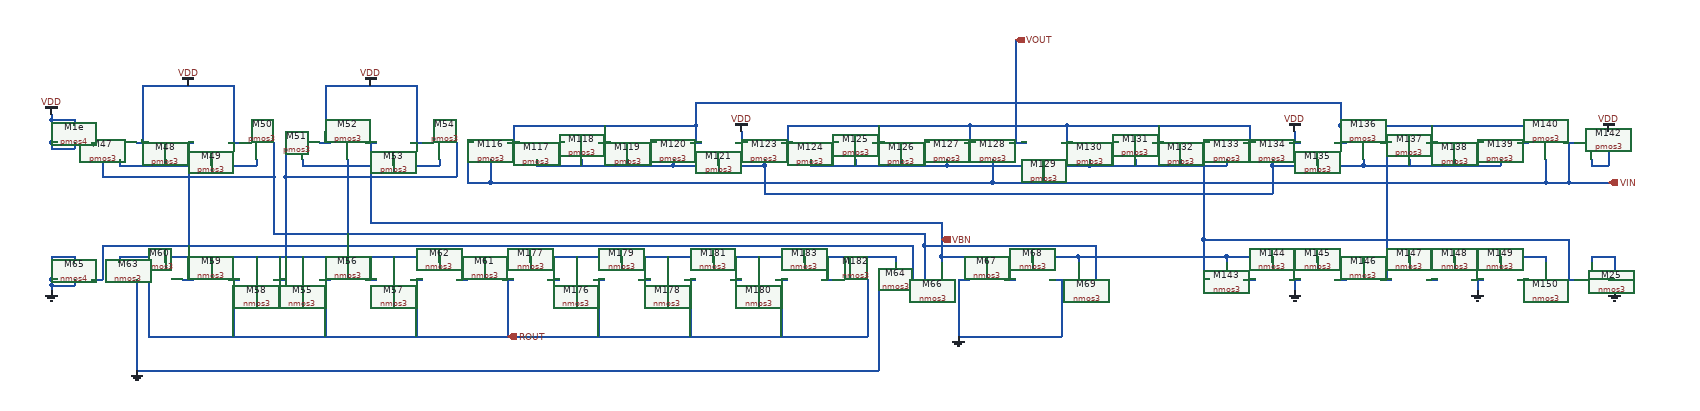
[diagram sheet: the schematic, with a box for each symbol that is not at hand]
v {xschem version=3.4.3 file_version=1.2
}
G {}
K {}
V {}
S {}
E {}
N -2510 230 -2510 240 {
lab=#net1}
N -2510 240 -2270 240 {
lab=#net1}
N -2270 230 -2270 240 {
lab=#net1}
N -2350 230 -2350 240 {
lab=#net1}
N -2430 230 -2430 240 {
lab=#net1}
N -2400 200 -2380 200 {
lab=#net1}
N -2390 200 -2390 240 {
lab=#net1}
N -2480 200 -2460 200 {
lab=VDD}
N -2320 200 -2300 200 {
lab=VDD}
N -2470 100 -2470 200 {
lab=VDD}
N -2470 100 -2310 100 {
lab=VDD}
N -2310 100 -2310 200 {
lab=VDD}
N -2540 200 -2540 260 {
lab=#net2}
N -2540 260 -2240 260 {
lab=#net2}
N -2240 200 -2240 260 {
lab=#net2}
N -2190 230 -2190 240 {
lab=#net2}
N -2190 240 -1950 240 {
lab=#net2}
N -1950 230 -1950 240 {
lab=#net2}
N -2030 230 -2030 240 {
lab=#net2}
N -2110 230 -2110 240 {
lab=#net2}
N -2080 200 -2060 200 {
lab=VBN}
N -2160 200 -2140 200 {
lab=VDD}
N -2000 200 -1980 200 {
lab=VDD}
N -2150 100 -2150 200 {
lab=VDD}
N -2150 100 -1990 100 {
lab=VDD}
N -1990 100 -1990 200 {
lab=VDD}
N -2220 200 -2220 260 {
lab=#net3}
N -2220 260 -1920 260 {
lab=#net3}
N -2190 400 -2190 410 {
lab=#net3}
N -2160 440 -2140 440 {
lab=VBN}
N -2110 400 -2110 410 {
lab=#net3}
N -2240 440 -2220 440 {
lab=#net3}
N -2080 440 -2060 440 {
lab=#net3}
N -2030 400 -2030 410 {
lab=#net3}
N -2270 400 -2270 410 {
lab=#net3}
N -2400 440 -2380 440 {
lab=#net3}
N -2320 440 -2300 440 {
lab=VBN}
N -2350 400 -2350 410 {
lab=#net3}
N -2430 400 -2430 410 {
lab=#net3}
N -1920 440 -1900 440 {
lab=#net3}
N -1870 400 -1870 410 {
lab=#net3}
N -1950 400 -1950 410 {
lab=#net3}
N -2000 440 -1980 440 {
lab=VBN}
N -2460 440 -2460 540 {
lab=VBN}
N -1990 440 -1990 540 {
lab=VBN}
N -2150 440 -2150 540 {
lab=VBN}
N -2310 440 -2310 540 {
lab=VBN}
N -2390 400 -2390 440 {
lab=#net3}
N -2230 400 -2230 440 {
lab=#net3}
N -2070 400 -2070 440 {
lab=#net3}
N -1910 400 -1910 440 {
lab=#net3}
N -2480 440 -2480 600 {
lab=GND}
N -1180 440 -1180 600 {
lab=GND}
N -2510 400 -2510 410 {
lab=#net3}
N -1150 400 -1150 410 {
lab=#net3}
N -1120 380 -1120 440 {
lab=#net1}
N -2540 380 -2540 440 {
lab=#net1}
N -2390 240 -2390 380 {
lab=#net1}
N -2590 160 -2590 170 {
lab=VDD}
N -2630 160 -2590 160 {
lab=VDD}
N -2630 160 -2630 200 {
lab=VDD}
N -2630 200 -2620 200 {
lab=VDD}
N -2590 200 -2590 210 {
lab=VDD}
N -2630 210 -2590 210 {
lab=VDD}
N -2630 200 -2630 210 {
lab=VDD}
N -2630 150 -2630 160 {
lab=VDD}
N -2560 200 -2540 200 {
lab=#net2}
N -2560 440 -2540 440 {
lab=#net1}
N -2590 440 -2590 450 {
lab=GND}
N -2630 450 -2590 450 {
lab=GND}
N -2630 440 -2630 450 {
lab=GND}
N -2630 440 -2620 440 {
lab=GND}
N -2590 400 -2590 410 {
lab=GND}
N -2630 400 -2590 400 {
lab=GND}
N -2630 400 -2630 440 {
lab=GND}
N -2630 450 -2630 460 {
lab=GND}
N -2220 260 -2220 400 {
lab=#net3}
N -1070 400 -1070 410 {
lab=VBN}
N -830 400 -830 410 {
lab=VBN}
N -990 400 -990 410 {
lab=VBN}
N -960 440 -940 440 {
lab=VBN}
N -910 400 -910 410 {
lab=VBN}
N -1070 400 -830 400 {
lab=VBN}
N -1100 380 -800 380 {
lab=#net2}
N -1100 380 -1100 440 {
lab=#net2}
N -860 440 -860 540 {
lab=GND}
N -1040 540 -860 540 {
lab=GND}
N -1040 440 -1040 540 {
lab=GND}
N -2070 200 -2070 280 {
lab=VBN}
N -2240 260 -2240 300 {
lab=#net2}
N -2110 240 -2110 300 {
lab=#net2}
N -1760 440 -1740 440 {
lab=#net3}
N -1710 400 -1710 410 {
lab=#net3}
N -1790 400 -1790 410 {
lab=#net3}
N -1840 440 -1820 440 {
lab=VBN}
N -1830 440 -1830 540 {
lab=VBN}
N -1750 400 -1750 440 {
lab=#net3}
N -1600 440 -1580 440 {
lab=#net3}
N -1550 400 -1550 410 {
lab=#net3}
N -1630 400 -1630 410 {
lab=#net3}
N -1680 440 -1660 440 {
lab=VBN}
N -1670 440 -1670 540 {
lab=VBN}
N -1590 400 -1590 440 {
lab=#net3}
N -1440 440 -1420 440 {
lab=#net3}
N -1390 400 -1390 410 {
lab=#net3}
N -1470 400 -1470 410 {
lab=#net3}
N -1520 440 -1500 440 {
lab=VBN}
N -1510 440 -1510 540 {
lab=VBN}
N -1430 400 -1430 440 {
lab=#net3}
N -1280 440 -1260 440 {
lab=#net3}
N -1230 400 -1230 410 {
lab=#net3}
N -1310 400 -1310 410 {
lab=#net3}
N -1360 440 -1340 440 {
lab=VBN}
N -1350 440 -1350 540 {
lab=VBN}
N -1270 400 -1270 440 {
lab=#net3}
N -1200 440 -1200 540 {
lab=VBN}
N -2460 540 -1200 540 {
lab=VBN}
N -2510 400 -1150 400 {
lab=#net3}
N -2480 600 -1180 600 {
lab=GND}
N -2540 380 -1120 380 {
lab=#net1}
N -2110 300 -2110 360 {
lab=#net2}
N -2240 300 -2240 360 {
lab=#net2}
N -1100 360 -1100 380 {
lab=#net2}
N -2070 340 -1070 340 {
lab=VBN}
N -2070 280 -2070 340 {
lab=VBN}
N -1070 340 -1070 400 {
lab=VBN}
N 70 400 70 410 {
lab=GND}
N 70 400 110 400 {
lab=GND}
N 100 440 110 440 {
lab=GND}
N 110 400 110 460 {
lab=GND}
N -1920 200 -1920 260 {
lab=#net3}
N -2240 360 -1100 360 {
lab=#net2}
N -1830 200 -1810 200 {
lab=#net4}
N -1750 200 -1730 200 {
lab=#net5}
N -1670 200 -1650 200 {
lab=#net4}
N -1590 200 -1570 200 {
lab=#net5}
N -1510 200 -1490 200 {
lab=#net4}
N -1430 200 -1410 200 {
lab=VDD}
N -1350 200 -1330 200 {
lab=#net6}
N -1270 200 -1250 200 {
lab=#net7}
N -1190 200 -1170 200 {
lab=#net6}
N -1110 200 -1090 200 {
lab=#net7}
N -1030 200 -1010 200 {
lab=#net6}
N -950 200 -930 200 {
lab=VOUT}
N -1900 200 -1890 200 {
lab=VIN}
N -1900 200 -1900 240 {
lab=VIN}
N -1860 230 -1860 240 {
lab=VIN}
N -1780 230 -1780 240 {
lab=#net5}
N -1700 230 -1700 240 {
lab=#net5}
N -1620 230 -1620 240 {
lab=#net5}
N -1540 230 -1540 240 {
lab=#net5}
N -1780 240 -1540 240 {
lab=#net5}
N -1820 170 -1820 200 {
lab=#net4}
N -1820 170 -1500 170 {
lab=#net4}
N -1500 170 -1500 200 {
lab=#net4}
N -1660 170 -1660 200 {
lab=#net4}
N -1740 200 -1740 240 {
lab=#net5}
N -1580 200 -1580 240 {
lab=#net5}
N -1540 240 -1380 240 {
lab=#net5}
N -1380 230 -1380 240 {
lab=#net5}
N -1460 230 -1460 240 {
lab=#net5}
N -1300 230 -1300 240 {
lab=#net7}
N -1300 240 -1060 240 {
lab=#net7}
N -1060 230 -1060 240 {
lab=#net7}
N -1220 230 -1220 240 {
lab=#net7}
N -1140 230 -1140 240 {
lab=#net7}
N -1420 180 -1420 200 {
lab=VDD}
N -1340 170 -1340 200 {
lab=#net6}
N -1340 170 -1020 170 {
lab=#net6}
N -1020 170 -1020 200 {
lab=#net6}
N -1180 170 -1180 200 {
lab=#net6}
N -1260 200 -1260 240 {
lab=#net7}
N -1100 200 -1100 240 {
lab=#net7}
N -860 200 -840 200 {
lab=#net6}
N -780 200 -760 200 {
lab=#net7}
N -700 200 -680 200 {
lab=#net6}
N -620 200 -600 200 {
lab=#net7}
N -540 200 -520 200 {
lab=#net6}
N -460 200 -440 200 {
lab=VDD}
N -380 200 -360 200 {
lab=#net4}
N -300 200 -280 200 {
lab=#net5}
N -220 200 -200 200 {
lab=#net4}
N -140 200 -120 200 {
lab=#net5}
N -60 200 -40 200 {
lab=#net4}
N 20 200 40 200 {
lab=VIN}
N -930 200 -920 200 {
lab=VOUT}
N -810 230 -810 240 {
lab=#net7}
N -730 230 -730 240 {
lab=#net7}
N -650 230 -650 240 {
lab=#net7}
N -570 230 -570 240 {
lab=#net7}
N -810 240 -570 240 {
lab=#net7}
N -850 170 -850 200 {
lab=#net6}
N -850 170 -530 170 {
lab=#net6}
N -530 170 -530 200 {
lab=#net6}
N -690 170 -690 200 {
lab=#net6}
N -770 200 -770 240 {
lab=#net7}
N -610 200 -610 240 {
lab=#net7}
N -410 230 -410 240 {
lab=#net5}
N -490 230 -490 240 {
lab=#net5}
N -330 230 -330 240 {
lab=#net5}
N -330 240 -90 240 {
lab=#net5}
N -90 230 -90 240 {
lab=#net5}
N -250 230 -250 240 {
lab=#net5}
N -170 230 -170 240 {
lab=#net5}
N -450 180 -450 200 {
lab=VDD}
N -370 170 -370 200 {
lab=#net4}
N -370 170 -50 170 {
lab=#net4}
N -50 170 -50 200 {
lab=#net4}
N -210 170 -210 200 {
lab=#net4}
N -290 200 -290 240 {
lab=#net5}
N -130 200 -130 240 {
lab=#net5}
N -490 240 -330 240 {
lab=#net5}
N -10 230 -10 240 {
lab=VIN}
N 30 200 30 240 {
lab=VIN}
N 70 230 70 240 {
lab=VDD}
N 70 240 100 240 {
lab=VDD}
N 100 200 100 240 {
lab=VDD}
N -540 440 -520 440 {
lab=#net8}
N -380 440 -360 440 {
lab=#net9}
N -460 440 -440 440 {
lab=GND}
N -220 440 -200 440 {
lab=#net10}
N -60 440 -40 440 {
lab=#net11}
N -140 440 -120 440 {
lab=GND}
N -300 440 -280 440 {
lab=#net5}
N -570 400 -570 410 {
lab=VBN}
N -490 400 -490 410 {
lab=VBN}
N -410 400 -410 410 {
lab=VBN}
N -330 400 -330 410 {
lab=VBN}
N -250 400 -250 410 {
lab=VBN}
N -170 400 -170 410 {
lab=VBN}
N -90 400 -90 410 {
lab=VBN}
N -10 400 -10 410 {
lab=VBN}
N -570 400 -10 400 {
lab=VBN}
N -450 440 -450 460 {
lab=GND}
N -130 440 -130 460 {
lab=GND}
N -1860 240 -1860 270 {
lab=VIN}
N -1900 240 -1900 270 {
lab=VIN}
N -1900 270 -1860 270 {
lab=VIN}
N -940 160 -940 200 {
lab=VOUT}
N -10 240 -10 270 {
lab=VIN}
N -980 270 -10 270 {
lab=VIN}
N 30 240 30 270 {
lab=VIN}
N -10 270 30 270 {
lab=VIN}
N -890 230 -890 270 {
lab=VIN}
N -1060 240 -810 240 {
lab=#net7}
N -980 230 -980 270 {
lab=VIN}
N 20 440 40 440 {
lab=#net7}
N -600 370 30 370 {
lab=#net7}
N 30 370 30 440 {
lab=#net7}
N -290 240 -290 430 {
lab=#net5}
N -610 440 -600 440 {
lab=#net7}
N -610 370 -610 440 {
lab=#net7}
N -610 370 -600 370 {
lab=#net7}
N -610 240 -610 360 {
lab=#net7}
N -1380 290 -490 290 {
lab=#net5}
N -490 240 -490 290 {
lab=#net5}
N -1860 270 -980 270 {
lab=VIN}
N -1380 240 -1380 290 {
lab=#net5}
N -1020 170 -850 170 {
lab=#net6}
N -1500 130 -1500 170 {
lab=#net4}
N -370 140 -370 170 {
lab=#net4}
N -370 130 -370 140 {
lab=#net4}
N -1500 130 -370 130 {
lab=#net4}
N 100 180 100 200 {
lab=VDD}
N -800 380 -800 440 {
lab=#net2}
N -940 20 -940 160 {
lab=VOUT}
N -610 360 -610 370 {
lab=#net7}
N -290 430 -290 440 {
lab=#net5}
N -830 400 -570 400 {
lab=VBN}
N -950 400 -950 440 {
lab=VBN}
N -880 440 -860 440 {
lab=GND}
N -1040 440 -1020 440 {
lab=GND}
N 30 270 100 270 {
lab=VIN}
C {madvlsi/pmos3.sym} -2510 200 3 0 {name=M47
L=\{L\}
W=\{W/2\}
body=VDD
nf=1
mult=1
ad="'int((nf+1)/2) * W/nf * 0.29'" 
pd="'2*int((nf+1)/2) * (W/nf + 0.29)'"
as="'int((nf+2)/2) * W/nf * 0.29'" 
ps="'2*int((nf+2)/2) * (W/nf + 0.29)'"
nrd="'0.29 / W'" nrs="'0.29 / W'"
sa=0 sb=0 sd=0
model=pfet_01v8
spiceprefix=X
}
C {madvlsi/pmos3.sym} -2430 200 3 0 {name=M48
L=\{L\}
W=\{W/2\}
body=VDD
nf=1
mult=1
ad="'int((nf+1)/2) * W/nf * 0.29'" 
pd="'2*int((nf+1)/2) * (W/nf + 0.29)'"
as="'int((nf+2)/2) * W/nf * 0.29'" 
ps="'2*int((nf+2)/2) * (W/nf + 0.29)'"
nrd="'0.29 / W'" nrs="'0.29 / W'"
sa=0 sb=0 sd=0
model=pfet_01v8
spiceprefix=X
}
C {madvlsi/pmos3.sym} -2350 200 3 0 {name=M49
L=\{L\}
W=\{W/2\}
body=VDD
nf=1
mult=1
ad="'int((nf+1)/2) * W/nf * 0.29'" 
pd="'2*int((nf+1)/2) * (W/nf + 0.29)'"
as="'int((nf+2)/2) * W/nf * 0.29'" 
ps="'2*int((nf+2)/2) * (W/nf + 0.29)'"
nrd="'0.29 / W'" nrs="'0.29 / W'"
sa=0 sb=0 sd=0
model=pfet_01v8
spiceprefix=X
}
C {madvlsi/pmos3.sym} -2270 200 3 0 {name=M50
L=\{L\}
W=\{W/2\}
body=VDD
nf=1
mult=1
ad="'int((nf+1)/2) * W/nf * 0.29'" 
pd="'2*int((nf+1)/2) * (W/nf + 0.29)'"
as="'int((nf+2)/2) * W/nf * 0.29'" 
ps="'2*int((nf+2)/2) * (W/nf + 0.29)'"
nrd="'0.29 / W'" nrs="'0.29 / W'"
sa=0 sb=0 sd=0
model=pfet_01v8
spiceprefix=X
}
C {madvlsi/pmos3.sym} -2190 200 3 0 {name=M51
L=\{L\}
W=\{W/2\}
body=VDD
nf=1
mult=1
ad="'int((nf+1)/2) * W/nf * 0.29'" 
pd="'2*int((nf+1)/2) * (W/nf + 0.29)'"
as="'int((nf+2)/2) * W/nf * 0.29'" 
ps="'2*int((nf+2)/2) * (W/nf + 0.29)'"
nrd="'0.29 / W'" nrs="'0.29 / W'"
sa=0 sb=0 sd=0
model=pfet_01v8
spiceprefix=X
}
C {madvlsi/pmos3.sym} -2110 200 3 0 {name=M52
L=\{L\}
W=\{W/2\}
body=VDD
nf=1
mult=1
ad="'int((nf+1)/2) * W/nf * 0.29'" 
pd="'2*int((nf+1)/2) * (W/nf + 0.29)'"
as="'int((nf+2)/2) * W/nf * 0.29'" 
ps="'2*int((nf+2)/2) * (W/nf + 0.29)'"
nrd="'0.29 / W'" nrs="'0.29 / W'"
sa=0 sb=0 sd=0
model=pfet_01v8
spiceprefix=X
}
C {madvlsi/pmos3.sym} -2030 200 3 0 {name=M53
L=\{L\}
W=\{W/2\}
body=VDD
nf=1
mult=1
ad="'int((nf+1)/2) * W/nf * 0.29'" 
pd="'2*int((nf+1)/2) * (W/nf + 0.29)'"
as="'int((nf+2)/2) * W/nf * 0.29'" 
ps="'2*int((nf+2)/2) * (W/nf + 0.29)'"
nrd="'0.29 / W'" nrs="'0.29 / W'"
sa=0 sb=0 sd=0
model=pfet_01v8
spiceprefix=X
}
C {madvlsi/pmos3.sym} -1950 200 3 0 {name=M54
L=\{L\}
W=\{W/2\}
body=VDD
nf=1
mult=1
ad="'int((nf+1)/2) * W/nf * 0.29'" 
pd="'2*int((nf+1)/2) * (W/nf + 0.29)'"
as="'int((nf+2)/2) * W/nf * 0.29'" 
ps="'2*int((nf+2)/2) * (W/nf + 0.29)'"
nrd="'0.29 / W'" nrs="'0.29 / W'"
sa=0 sb=0 sd=0
model=pfet_01v8
spiceprefix=X
}
C {madvlsi/nmos3.sym} -2190 440 1 0 {name=M55
L=\{L\}
W=\{W/2\}
body=GND
nf=1
mult=1
ad="'int((nf+1)/2) * W/nf * 0.29'" 
pd="'2*int((nf+1)/2) * (W/nf + 0.29)'"
as="'int((nf+2)/2) * W/nf * 0.29'" 
ps="'2*int((nf+2)/2) * (W/nf + 0.29)'"
nrd="'0.29 / W'" nrs="'0.29 / W'"
sa=0 sb=0 sd=0
model=nfet_01v8
spiceprefix=X
}
C {madvlsi/nmos3.sym} -2110 440 1 0 {name=M56
L=\{L\}
W=\{W/2\}
body=GND
nf=1
mult=1
ad="'int((nf+1)/2) * W/nf * 0.29'" 
pd="'2*int((nf+1)/2) * (W/nf + 0.29)'"
as="'int((nf+2)/2) * W/nf * 0.29'" 
ps="'2*int((nf+2)/2) * (W/nf + 0.29)'"
nrd="'0.29 / W'" nrs="'0.29 / W'"
sa=0 sb=0 sd=0
model=nfet_01v8
spiceprefix=X
}
C {madvlsi/nmos3.sym} -2030 440 1 0 {name=M57
L=\{L\}
W=\{W/2\}
body=GND
nf=1
mult=1
ad="'int((nf+1)/2) * W/nf * 0.29'" 
pd="'2*int((nf+1)/2) * (W/nf + 0.29)'"
as="'int((nf+2)/2) * W/nf * 0.29'" 
ps="'2*int((nf+2)/2) * (W/nf + 0.29)'"
nrd="'0.29 / W'" nrs="'0.29 / W'"
sa=0 sb=0 sd=0
model=nfet_01v8
spiceprefix=X
}
C {madvlsi/nmos3.sym} -2270 440 1 0 {name=M58
L=\{L\}
W=\{W/2\}
body=GND
nf=1
mult=1
ad="'int((nf+1)/2) * W/nf * 0.29'" 
pd="'2*int((nf+1)/2) * (W/nf + 0.29)'"
as="'int((nf+2)/2) * W/nf * 0.29'" 
ps="'2*int((nf+2)/2) * (W/nf + 0.29)'"
nrd="'0.29 / W'" nrs="'0.29 / W'"
sa=0 sb=0 sd=0
model=nfet_01v8
spiceprefix=X
}
C {madvlsi/nmos3.sym} -2350 440 1 0 {name=M59
L=\{L\}
W=\{W/2\}
body=GND
nf=1
mult=1
ad="'int((nf+1)/2) * W/nf * 0.29'" 
pd="'2*int((nf+1)/2) * (W/nf + 0.29)'"
as="'int((nf+2)/2) * W/nf * 0.29'" 
ps="'2*int((nf+2)/2) * (W/nf + 0.29)'"
nrd="'0.29 / W'" nrs="'0.29 / W'"
sa=0 sb=0 sd=0
model=nfet_01v8
spiceprefix=X
}
C {madvlsi/nmos3.sym} -2430 440 1 0 {name=M60
L=\{L\}
W=\{W/2\}
body=GND
nf=1
mult=1
ad="'int((nf+1)/2) * W/nf * 0.29'" 
pd="'2*int((nf+1)/2) * (W/nf + 0.29)'"
as="'int((nf+2)/2) * W/nf * 0.29'" 
ps="'2*int((nf+2)/2) * (W/nf + 0.29)'"
nrd="'0.29 / W'" nrs="'0.29 / W'"
sa=0 sb=0 sd=0
model=nfet_01v8
spiceprefix=X
}
C {madvlsi/nmos3.sym} -1870 440 1 0 {name=M61
L=\{L\}
W=\{W/2\}
body=GND
nf=1
mult=1
ad="'int((nf+1)/2) * W/nf * 0.29'" 
pd="'2*int((nf+1)/2) * (W/nf + 0.29)'"
as="'int((nf+2)/2) * W/nf * 0.29'" 
ps="'2*int((nf+2)/2) * (W/nf + 0.29)'"
nrd="'0.29 / W'" nrs="'0.29 / W'"
sa=0 sb=0 sd=0
model=nfet_01v8
spiceprefix=X
}
C {madvlsi/nmos3.sym} -1950 440 1 0 {name=M62
L=\{L\}
W=\{W/2\}
body=GND
nf=1
mult=1
ad="'int((nf+1)/2) * W/nf * 0.29'" 
pd="'2*int((nf+1)/2) * (W/nf + 0.29)'"
as="'int((nf+2)/2) * W/nf * 0.29'" 
ps="'2*int((nf+2)/2) * (W/nf + 0.29)'"
nrd="'0.29 / W'" nrs="'0.29 / W'"
sa=0 sb=0 sd=0
model=nfet_01v8
spiceprefix=X
}
C {madvlsi/nmos3.sym} -2510 440 1 0 {name=M63
L=\{L\}
W=\{W/2\}
body=GND
nf=1
mult=1
ad="'int((nf+1)/2) * W/nf * 0.29'" 
pd="'2*int((nf+1)/2) * (W/nf + 0.29)'"
as="'int((nf+2)/2) * W/nf * 0.29'" 
ps="'2*int((nf+2)/2) * (W/nf + 0.29)'"
nrd="'0.29 / W'" nrs="'0.29 / W'"
sa=0 sb=0 sd=0
model=nfet_01v8
spiceprefix=X
}
C {madvlsi/nmos3.sym} -1150 440 1 0 {name=M64
L=\{L\}
W=\{W/2\}
body=GND
nf=1
mult=1
ad="'int((nf+1)/2) * W/nf * 0.29'" 
pd="'2*int((nf+1)/2) * (W/nf + 0.29)'"
as="'int((nf+2)/2) * W/nf * 0.29'" 
ps="'2*int((nf+2)/2) * (W/nf + 0.29)'"
nrd="'0.29 / W'" nrs="'0.29 / W'"
sa=0 sb=0 sd=0
model=nfet_01v8
spiceprefix=X
}
C {madvlsi/pmos4.sym} -2590 200 1 0 {name=M1e
L=\{L\}
W=\{W/2\}
nf=1
mult=1
ad="'int((nf+1)/2) * W/nf * 0.29'" 
pd="'2*int((nf+1)/2) * (W/nf + 0.29)'"
as="'int((nf+2)/2) * W/nf * 0.29'" 
ps="'2*int((nf+2)/2) * (W/nf + 0.29)'"
nrd="'0.29 / W'" nrs="'0.29 / W'"
sa=0 sb=0 sd=0
model=pfet_01v8
spiceprefix=X
}
C {madvlsi/vdd.sym} -2630 150 0 0 {name=l24 lab=VDD}
C {madvlsi/nmos4.sym} -2590 440 1 0 {name=M65
L=\{L\}
W=\{W/2\}
nf=1 
mult=1
ad="'int((nf+1)/2) * W/nf * 0.29'" 
pd="'2*int((nf+1)/2) * (W/nf + 0.29)'"
as="'int((nf+2)/2) * W/nf * 0.29'" 
ps="'2*int((nf+2)/2) * (W/nf + 0.29)'"
nrd="'0.29 / W'" nrs="'0.29 / W'"
sa=0 sb=0 sd=0
model=nfet_01v8
spiceprefix=X
}
C {madvlsi/gnd.sym} -2630 460 0 0 {name=l33 lab=GND}
C {madvlsi/nmos3.sym} -1070 440 1 0 {name=M66
L=\{L\}
W=\{W/2\}
body=GND
nf=1
mult=1
ad="'int((nf+1)/2) * W/nf * 0.29'" 
pd="'2*int((nf+1)/2) * (W/nf + 0.29)'"
as="'int((nf+2)/2) * W/nf * 0.29'" 
ps="'2*int((nf+2)/2) * (W/nf + 0.29)'"
nrd="'0.29 / W'" nrs="'0.29 / W'"
sa=0 sb=0 sd=0
model=nfet_01v8
spiceprefix=X
}
C {madvlsi/nmos3.sym} -990 440 1 0 {name=M67
L=\{L\}
W=\{W/2\}
body=GND
nf=1
mult=1
ad="'int((nf+1)/2) * W/nf * 0.29'" 
pd="'2*int((nf+1)/2) * (W/nf + 0.29)'"
as="'int((nf+2)/2) * W/nf * 0.29'" 
ps="'2*int((nf+2)/2) * (W/nf + 0.29)'"
nrd="'0.29 / W'" nrs="'0.29 / W'"
sa=0 sb=0 sd=0
model=nfet_01v8
spiceprefix=X
}
C {madvlsi/nmos3.sym} -910 440 1 0 {name=M68
L=\{L\}
W=\{W/2\}
body=GND
nf=1
mult=1
ad="'int((nf+1)/2) * W/nf * 0.29'" 
pd="'2*int((nf+1)/2) * (W/nf + 0.29)'"
as="'int((nf+2)/2) * W/nf * 0.29'" 
ps="'2*int((nf+2)/2) * (W/nf + 0.29)'"
nrd="'0.29 / W'" nrs="'0.29 / W'"
sa=0 sb=0 sd=0
model=nfet_01v8
spiceprefix=X
}
C {madvlsi/nmos3.sym} -830 440 1 0 {name=M69
L=\{L\}
W=\{W/2\}
body=GND
nf=1
mult=1
ad="'int((nf+1)/2) * W/nf * 0.29'" 
pd="'2*int((nf+1)/2) * (W/nf + 0.29)'"
as="'int((nf+2)/2) * W/nf * 0.29'" 
ps="'2*int((nf+2)/2) * (W/nf + 0.29)'"
nrd="'0.29 / W'" nrs="'0.29 / W'"
sa=0 sb=0 sd=0
model=nfet_01v8
spiceprefix=X
}
C {madvlsi/nmos3.sym} -1710 440 1 0 {name=M176
L=\{L\}
W=\{W/2\}
body=GND
nf=1
mult=1
ad="'int((nf+1)/2) * W/nf * 0.29'" 
pd="'2*int((nf+1)/2) * (W/nf + 0.29)'"
as="'int((nf+2)/2) * W/nf * 0.29'" 
ps="'2*int((nf+2)/2) * (W/nf + 0.29)'"
nrd="'0.29 / W'" nrs="'0.29 / W'"
sa=0 sb=0 sd=0
model=nfet_01v8
spiceprefix=X
}
C {madvlsi/nmos3.sym} -1790 440 1 0 {name=M177
L=\{L\}
W=\{W/2\}
body=GND
nf=1
mult=1
ad="'int((nf+1)/2) * W/nf * 0.29'" 
pd="'2*int((nf+1)/2) * (W/nf + 0.29)'"
as="'int((nf+2)/2) * W/nf * 0.29'" 
ps="'2*int((nf+2)/2) * (W/nf + 0.29)'"
nrd="'0.29 / W'" nrs="'0.29 / W'"
sa=0 sb=0 sd=0
model=nfet_01v8
spiceprefix=X
}
C {madvlsi/nmos3.sym} -1550 440 1 0 {name=M178
L=\{L\}
W=\{W/2\}
body=GND
nf=1
mult=1
ad="'int((nf+1)/2) * W/nf * 0.29'" 
pd="'2*int((nf+1)/2) * (W/nf + 0.29)'"
as="'int((nf+2)/2) * W/nf * 0.29'" 
ps="'2*int((nf+2)/2) * (W/nf + 0.29)'"
nrd="'0.29 / W'" nrs="'0.29 / W'"
sa=0 sb=0 sd=0
model=nfet_01v8
spiceprefix=X
}
C {madvlsi/nmos3.sym} -1630 440 1 0 {name=M179
L=\{L\}
W=\{W/2\}
body=GND
nf=1
mult=1
ad="'int((nf+1)/2) * W/nf * 0.29'" 
pd="'2*int((nf+1)/2) * (W/nf + 0.29)'"
as="'int((nf+2)/2) * W/nf * 0.29'" 
ps="'2*int((nf+2)/2) * (W/nf + 0.29)'"
nrd="'0.29 / W'" nrs="'0.29 / W'"
sa=0 sb=0 sd=0
model=nfet_01v8
spiceprefix=X
}
C {madvlsi/nmos3.sym} -1390 440 1 0 {name=M180
L=\{L\}
W=\{W/2\}
body=GND
nf=1
mult=1
ad="'int((nf+1)/2) * W/nf * 0.29'" 
pd="'2*int((nf+1)/2) * (W/nf + 0.29)'"
as="'int((nf+2)/2) * W/nf * 0.29'" 
ps="'2*int((nf+2)/2) * (W/nf + 0.29)'"
nrd="'0.29 / W'" nrs="'0.29 / W'"
sa=0 sb=0 sd=0
model=nfet_01v8
spiceprefix=X
}
C {madvlsi/nmos3.sym} -1470 440 1 0 {name=M181
L=\{L\}
W=\{W/2\}
body=GND
nf=1
mult=1
ad="'int((nf+1)/2) * W/nf * 0.29'" 
pd="'2*int((nf+1)/2) * (W/nf + 0.29)'"
as="'int((nf+2)/2) * W/nf * 0.29'" 
ps="'2*int((nf+2)/2) * (W/nf + 0.29)'"
nrd="'0.29 / W'" nrs="'0.29 / W'"
sa=0 sb=0 sd=0
model=nfet_01v8
spiceprefix=X
}
C {madvlsi/nmos3.sym} -1230 440 1 0 {name=M182
L=\{L\}
W=\{W/2\}
body=GND
nf=1
mult=1
ad="'int((nf+1)/2) * W/nf * 0.29'" 
pd="'2*int((nf+1)/2) * (W/nf + 0.29)'"
as="'int((nf+2)/2) * W/nf * 0.29'" 
ps="'2*int((nf+2)/2) * (W/nf + 0.29)'"
nrd="'0.29 / W'" nrs="'0.29 / W'"
sa=0 sb=0 sd=0
model=nfet_01v8
spiceprefix=X
}
C {madvlsi/nmos3.sym} -1310 440 1 0 {name=M183
L=\{L\}
W=\{W/2\}
body=GND
nf=1
mult=1
ad="'int((nf+1)/2) * W/nf * 0.29'" 
pd="'2*int((nf+1)/2) * (W/nf + 0.29)'"
as="'int((nf+2)/2) * W/nf * 0.29'" 
ps="'2*int((nf+2)/2) * (W/nf + 0.29)'"
nrd="'0.29 / W'" nrs="'0.29 / W'"
sa=0 sb=0 sd=0
model=nfet_01v8
spiceprefix=X
}
C {madvlsi/gnd.sym} -2480 600 0 0 {name=l41 lab=GND}
C {madvlsi/gnd.sym} -1040 540 0 0 {name=l43 lab=GND}
C {madvlsi/vdd.sym} -2390 100 0 0 {name=l45 lab=VDD}
C {madvlsi/vdd.sym} -2070 100 0 0 {name=l46 lab=VDD}
C {madvlsi/gnd.sym} 110 460 0 0 {name=l25 lab=GND}
C {madvlsi/pmos3.sym} -1860 200 3 0 {name=M116
L=\{L\}
W=\{W/2\}
body=VDD
nf=1
mult=1
ad="'int((nf+1)/2) * W/nf * 0.29'" 
pd="'2*int((nf+1)/2) * (W/nf + 0.29)'"
as="'int((nf+2)/2) * W/nf * 0.29'" 
ps="'2*int((nf+2)/2) * (W/nf + 0.29)'"
nrd="'0.29 / W'" nrs="'0.29 / W'"
sa=0 sb=0 sd=0
model=pfet_01v8
spiceprefix=X
}
C {madvlsi/pmos3.sym} -1780 200 3 0 {name=M117
L=\{L\}
W=\{W/2\}
body=VDD
nf=1
mult=1
ad="'int((nf+1)/2) * W/nf * 0.29'" 
pd="'2*int((nf+1)/2) * (W/nf + 0.29)'"
as="'int((nf+2)/2) * W/nf * 0.29'" 
ps="'2*int((nf+2)/2) * (W/nf + 0.29)'"
nrd="'0.29 / W'" nrs="'0.29 / W'"
sa=0 sb=0 sd=0
model=pfet_01v8
spiceprefix=X
}
C {madvlsi/pmos3.sym} -1700 200 3 0 {name=M118
L=\{L\}
W=\{W/2\}
body=VDD
nf=1
mult=1
ad="'int((nf+1)/2) * W/nf * 0.29'" 
pd="'2*int((nf+1)/2) * (W/nf + 0.29)'"
as="'int((nf+2)/2) * W/nf * 0.29'" 
ps="'2*int((nf+2)/2) * (W/nf + 0.29)'"
nrd="'0.29 / W'" nrs="'0.29 / W'"
sa=0 sb=0 sd=0
model=pfet_01v8
spiceprefix=X
}
C {madvlsi/pmos3.sym} -1620 200 3 0 {name=M119
L=\{L\}
W=\{W/2\}
body=VDD
nf=1
mult=1
ad="'int((nf+1)/2) * W/nf * 0.29'" 
pd="'2*int((nf+1)/2) * (W/nf + 0.29)'"
as="'int((nf+2)/2) * W/nf * 0.29'" 
ps="'2*int((nf+2)/2) * (W/nf + 0.29)'"
nrd="'0.29 / W'" nrs="'0.29 / W'"
sa=0 sb=0 sd=0
model=pfet_01v8
spiceprefix=X
}
C {madvlsi/pmos3.sym} -1540 200 3 0 {name=M120
L=\{L\}
W=\{W/2\}
body=VDD
nf=1
mult=1
ad="'int((nf+1)/2) * W/nf * 0.29'" 
pd="'2*int((nf+1)/2) * (W/nf + 0.29)'"
as="'int((nf+2)/2) * W/nf * 0.29'" 
ps="'2*int((nf+2)/2) * (W/nf + 0.29)'"
nrd="'0.29 / W'" nrs="'0.29 / W'"
sa=0 sb=0 sd=0
model=pfet_01v8
spiceprefix=X
}
C {madvlsi/pmos3.sym} -1460 200 3 0 {name=M121
L=\{L\}
W=\{W/2\}
body=VDD
nf=1
mult=1
ad="'int((nf+1)/2) * W/nf * 0.29'" 
pd="'2*int((nf+1)/2) * (W/nf + 0.29)'"
as="'int((nf+2)/2) * W/nf * 0.29'" 
ps="'2*int((nf+2)/2) * (W/nf + 0.29)'"
nrd="'0.29 / W'" nrs="'0.29 / W'"
sa=0 sb=0 sd=0
model=pfet_01v8
spiceprefix=X
}
C {madvlsi/pmos3.sym} -1380 200 3 0 {name=M123
L=\{L\}
W=\{W/2\}
body=VDD
nf=1
mult=1
ad="'int((nf+1)/2) * W/nf * 0.29'" 
pd="'2*int((nf+1)/2) * (W/nf + 0.29)'"
as="'int((nf+2)/2) * W/nf * 0.29'" 
ps="'2*int((nf+2)/2) * (W/nf + 0.29)'"
nrd="'0.29 / W'" nrs="'0.29 / W'"
sa=0 sb=0 sd=0
model=pfet_01v8
spiceprefix=X
}
C {madvlsi/pmos3.sym} -1300 200 3 0 {name=M124
L=\{L\}
W=\{W/2\}
body=VDD
nf=1
mult=1
ad="'int((nf+1)/2) * W/nf * 0.29'" 
pd="'2*int((nf+1)/2) * (W/nf + 0.29)'"
as="'int((nf+2)/2) * W/nf * 0.29'" 
ps="'2*int((nf+2)/2) * (W/nf + 0.29)'"
nrd="'0.29 / W'" nrs="'0.29 / W'"
sa=0 sb=0 sd=0
model=pfet_01v8
spiceprefix=X
}
C {madvlsi/pmos3.sym} -1220 200 3 0 {name=M125
L=\{L\}
W=\{W/2\}
body=VDD
nf=1
mult=1
ad="'int((nf+1)/2) * W/nf * 0.29'" 
pd="'2*int((nf+1)/2) * (W/nf + 0.29)'"
as="'int((nf+2)/2) * W/nf * 0.29'" 
ps="'2*int((nf+2)/2) * (W/nf + 0.29)'"
nrd="'0.29 / W'" nrs="'0.29 / W'"
sa=0 sb=0 sd=0
model=pfet_01v8
spiceprefix=X
}
C {madvlsi/pmos3.sym} -1140 200 3 0 {name=M126
L=\{L\}
W=\{W/2\}
body=VDD
nf=1
mult=1
ad="'int((nf+1)/2) * W/nf * 0.29'" 
pd="'2*int((nf+1)/2) * (W/nf + 0.29)'"
as="'int((nf+2)/2) * W/nf * 0.29'" 
ps="'2*int((nf+2)/2) * (W/nf + 0.29)'"
nrd="'0.29 / W'" nrs="'0.29 / W'"
sa=0 sb=0 sd=0
model=pfet_01v8
spiceprefix=X
}
C {madvlsi/pmos3.sym} -1060 200 3 0 {name=M127
L=\{L\}
W=\{W/2\}
body=VDD
nf=1
mult=1
ad="'int((nf+1)/2) * W/nf * 0.29'" 
pd="'2*int((nf+1)/2) * (W/nf + 0.29)'"
as="'int((nf+2)/2) * W/nf * 0.29'" 
ps="'2*int((nf+2)/2) * (W/nf + 0.29)'"
nrd="'0.29 / W'" nrs="'0.29 / W'"
sa=0 sb=0 sd=0
model=pfet_01v8
spiceprefix=X
}
C {madvlsi/pmos3.sym} -980 200 3 0 {name=M128
L=\{L\}
W=\{W/2\}
body=VDD
nf=1
mult=1
ad="'int((nf+1)/2) * W/nf * 0.29'" 
pd="'2*int((nf+1)/2) * (W/nf + 0.29)'"
as="'int((nf+2)/2) * W/nf * 0.29'" 
ps="'2*int((nf+2)/2) * (W/nf + 0.29)'"
nrd="'0.29 / W'" nrs="'0.29 / W'"
sa=0 sb=0 sd=0
model=pfet_01v8
spiceprefix=X
}
C {madvlsi/vdd.sym} -1420 180 0 0 {name=l29 lab=VDD}
C {madvlsi/pmos3.sym} -890 200 3 0 {name=M129
L=\{L\}
W=\{W/2\}
body=VDD
nf=1
mult=1
ad="'int((nf+1)/2) * W/nf * 0.29'" 
pd="'2*int((nf+1)/2) * (W/nf + 0.29)'"
as="'int((nf+2)/2) * W/nf * 0.29'" 
ps="'2*int((nf+2)/2) * (W/nf + 0.29)'"
nrd="'0.29 / W'" nrs="'0.29 / W'"
sa=0 sb=0 sd=0
model=pfet_01v8
spiceprefix=X
}
C {madvlsi/pmos3.sym} -810 200 3 0 {name=M130
L=\{L\}
W=\{W/2\}
body=VDD
nf=1
mult=1
ad="'int((nf+1)/2) * W/nf * 0.29'" 
pd="'2*int((nf+1)/2) * (W/nf + 0.29)'"
as="'int((nf+2)/2) * W/nf * 0.29'" 
ps="'2*int((nf+2)/2) * (W/nf + 0.29)'"
nrd="'0.29 / W'" nrs="'0.29 / W'"
sa=0 sb=0 sd=0
model=pfet_01v8
spiceprefix=X
}
C {madvlsi/pmos3.sym} -730 200 3 0 {name=M131
L=\{L\}
W=\{W/2\}
body=VDD
nf=1
mult=1
ad="'int((nf+1)/2) * W/nf * 0.29'" 
pd="'2*int((nf+1)/2) * (W/nf + 0.29)'"
as="'int((nf+2)/2) * W/nf * 0.29'" 
ps="'2*int((nf+2)/2) * (W/nf + 0.29)'"
nrd="'0.29 / W'" nrs="'0.29 / W'"
sa=0 sb=0 sd=0
model=pfet_01v8
spiceprefix=X
}
C {madvlsi/pmos3.sym} -650 200 3 0 {name=M132
L=\{L\}
W=\{W/2\}
body=VDD
nf=1
mult=1
ad="'int((nf+1)/2) * W/nf * 0.29'" 
pd="'2*int((nf+1)/2) * (W/nf + 0.29)'"
as="'int((nf+2)/2) * W/nf * 0.29'" 
ps="'2*int((nf+2)/2) * (W/nf + 0.29)'"
nrd="'0.29 / W'" nrs="'0.29 / W'"
sa=0 sb=0 sd=0
model=pfet_01v8
spiceprefix=X
}
C {madvlsi/pmos3.sym} -570 200 3 0 {name=M133
L=\{L\}
W=\{W/2\}
body=VDD
nf=1
mult=1
ad="'int((nf+1)/2) * W/nf * 0.29'" 
pd="'2*int((nf+1)/2) * (W/nf + 0.29)'"
as="'int((nf+2)/2) * W/nf * 0.29'" 
ps="'2*int((nf+2)/2) * (W/nf + 0.29)'"
nrd="'0.29 / W'" nrs="'0.29 / W'"
sa=0 sb=0 sd=0
model=pfet_01v8
spiceprefix=X
}
C {madvlsi/pmos3.sym} -490 200 3 0 {name=M134
L=\{L\}
W=\{W/2\}
body=VDD
nf=1
mult=1
ad="'int((nf+1)/2) * W/nf * 0.29'" 
pd="'2*int((nf+1)/2) * (W/nf + 0.29)'"
as="'int((nf+2)/2) * W/nf * 0.29'" 
ps="'2*int((nf+2)/2) * (W/nf + 0.29)'"
nrd="'0.29 / W'" nrs="'0.29 / W'"
sa=0 sb=0 sd=0
model=pfet_01v8
spiceprefix=X
}
C {madvlsi/pmos3.sym} -410 200 3 0 {name=M135
L=\{L\}
W=\{W/2\}
body=VDD
nf=1
mult=1
ad="'int((nf+1)/2) * W/nf * 0.29'" 
pd="'2*int((nf+1)/2) * (W/nf + 0.29)'"
as="'int((nf+2)/2) * W/nf * 0.29'" 
ps="'2*int((nf+2)/2) * (W/nf + 0.29)'"
nrd="'0.29 / W'" nrs="'0.29 / W'"
sa=0 sb=0 sd=0
model=pfet_01v8
spiceprefix=X
}
C {madvlsi/pmos3.sym} -330 200 3 0 {name=M136
L=\{L\}
W=\{W/2\}
body=VDD
nf=1
mult=1
ad="'int((nf+1)/2) * W/nf * 0.29'" 
pd="'2*int((nf+1)/2) * (W/nf + 0.29)'"
as="'int((nf+2)/2) * W/nf * 0.29'" 
ps="'2*int((nf+2)/2) * (W/nf + 0.29)'"
nrd="'0.29 / W'" nrs="'0.29 / W'"
sa=0 sb=0 sd=0
model=pfet_01v8
spiceprefix=X
}
C {madvlsi/pmos3.sym} -250 200 3 0 {name=M137
L=\{L\}
W=\{W/2\}
body=VDD
nf=1
mult=1
ad="'int((nf+1)/2) * W/nf * 0.29'" 
pd="'2*int((nf+1)/2) * (W/nf + 0.29)'"
as="'int((nf+2)/2) * W/nf * 0.29'" 
ps="'2*int((nf+2)/2) * (W/nf + 0.29)'"
nrd="'0.29 / W'" nrs="'0.29 / W'"
sa=0 sb=0 sd=0
model=pfet_01v8
spiceprefix=X
}
C {madvlsi/pmos3.sym} -170 200 3 0 {name=M138
L=\{L\}
W=\{W/2\}
body=VDD
nf=1
mult=1
ad="'int((nf+1)/2) * W/nf * 0.29'" 
pd="'2*int((nf+1)/2) * (W/nf + 0.29)'"
as="'int((nf+2)/2) * W/nf * 0.29'" 
ps="'2*int((nf+2)/2) * (W/nf + 0.29)'"
nrd="'0.29 / W'" nrs="'0.29 / W'"
sa=0 sb=0 sd=0
model=pfet_01v8
spiceprefix=X
}
C {madvlsi/pmos3.sym} -90 200 3 0 {name=M139
L=\{L\}
W=\{W/2\}
body=VDD
nf=1
mult=1
ad="'int((nf+1)/2) * W/nf * 0.29'" 
pd="'2*int((nf+1)/2) * (W/nf + 0.29)'"
as="'int((nf+2)/2) * W/nf * 0.29'" 
ps="'2*int((nf+2)/2) * (W/nf + 0.29)'"
nrd="'0.29 / W'" nrs="'0.29 / W'"
sa=0 sb=0 sd=0
model=pfet_01v8
spiceprefix=X
}
C {madvlsi/pmos3.sym} -10 200 3 0 {name=M140
L=\{L\}
W=\{W/2\}
body=VDD
nf=1
mult=1
ad="'int((nf+1)/2) * W/nf * 0.29'" 
pd="'2*int((nf+1)/2) * (W/nf + 0.29)'"
as="'int((nf+2)/2) * W/nf * 0.29'" 
ps="'2*int((nf+2)/2) * (W/nf + 0.29)'"
nrd="'0.29 / W'" nrs="'0.29 / W'"
sa=0 sb=0 sd=0
model=pfet_01v8
spiceprefix=X
}
C {madvlsi/vdd.sym} -450 180 0 0 {name=l31 lab=VDD}
C {madvlsi/pmos3.sym} 70 200 3 0 {name=M142
L=\{L\}
W=\{W/2\}
body=VDD
nf=1
mult=1
ad="'int((nf+1)/2) * W/nf * 0.29'" 
pd="'2*int((nf+1)/2) * (W/nf + 0.29)'"
as="'int((nf+2)/2) * W/nf * 0.29'" 
ps="'2*int((nf+2)/2) * (W/nf + 0.29)'"
nrd="'0.29 / W'" nrs="'0.29 / W'"
sa=0 sb=0 sd=0
model=pfet_01v8
spiceprefix=X
}
C {madvlsi/nmos3.sym} -570 440 1 0 {name=M143
L=\{L\}
W=\{W/2\}
body=GND
nf=1
mult=1
ad="'int((nf+1)/2) * W/nf * 0.29'" 
pd="'2*int((nf+1)/2) * (W/nf + 0.29)'"
as="'int((nf+2)/2) * W/nf * 0.29'" 
ps="'2*int((nf+2)/2) * (W/nf + 0.29)'"
nrd="'0.29 / W'" nrs="'0.29 / W'"
sa=0 sb=0 sd=0
model=nfet_01v8
spiceprefix=X
}
C {madvlsi/nmos3.sym} -490 440 1 0 {name=M144
L=\{L\}
W=\{W/2\}
body=GND
nf=1
mult=1
ad="'int((nf+1)/2) * W/nf * 0.29'" 
pd="'2*int((nf+1)/2) * (W/nf + 0.29)'"
as="'int((nf+2)/2) * W/nf * 0.29'" 
ps="'2*int((nf+2)/2) * (W/nf + 0.29)'"
nrd="'0.29 / W'" nrs="'0.29 / W'"
sa=0 sb=0 sd=0
model=nfet_01v8
spiceprefix=X
}
C {madvlsi/nmos3.sym} -410 440 1 0 {name=M145
L=\{L\}
W=\{W/2\}
body=GND
nf=1
mult=1
ad="'int((nf+1)/2) * W/nf * 0.29'" 
pd="'2*int((nf+1)/2) * (W/nf + 0.29)'"
as="'int((nf+2)/2) * W/nf * 0.29'" 
ps="'2*int((nf+2)/2) * (W/nf + 0.29)'"
nrd="'0.29 / W'" nrs="'0.29 / W'"
sa=0 sb=0 sd=0
model=nfet_01v8
spiceprefix=X
}
C {madvlsi/nmos3.sym} -330 440 1 0 {name=M146
L=\{L\}
W=\{W/2\}
body=GND
nf=1
mult=1
ad="'int((nf+1)/2) * W/nf * 0.29'" 
pd="'2*int((nf+1)/2) * (W/nf + 0.29)'"
as="'int((nf+2)/2) * W/nf * 0.29'" 
ps="'2*int((nf+2)/2) * (W/nf + 0.29)'"
nrd="'0.29 / W'" nrs="'0.29 / W'"
sa=0 sb=0 sd=0
model=nfet_01v8
spiceprefix=X
}
C {madvlsi/nmos3.sym} -250 440 1 0 {name=M147
L=\{L\}
W=\{W/2\}
body=GND
nf=1
mult=1
ad="'int((nf+1)/2) * W/nf * 0.29'" 
pd="'2*int((nf+1)/2) * (W/nf + 0.29)'"
as="'int((nf+2)/2) * W/nf * 0.29'" 
ps="'2*int((nf+2)/2) * (W/nf + 0.29)'"
nrd="'0.29 / W'" nrs="'0.29 / W'"
sa=0 sb=0 sd=0
model=nfet_01v8
spiceprefix=X
}
C {madvlsi/nmos3.sym} -170 440 1 0 {name=M148
L=\{L\}
W=\{W/2\}
body=GND
nf=1
mult=1
ad="'int((nf+1)/2) * W/nf * 0.29'" 
pd="'2*int((nf+1)/2) * (W/nf + 0.29)'"
as="'int((nf+2)/2) * W/nf * 0.29'" 
ps="'2*int((nf+2)/2) * (W/nf + 0.29)'"
nrd="'0.29 / W'" nrs="'0.29 / W'"
sa=0 sb=0 sd=0
model=nfet_01v8
spiceprefix=X
}
C {madvlsi/nmos3.sym} -90 440 1 0 {name=M149
L=\{L\}
W=\{W/2\}
body=GND
nf=1
mult=1
ad="'int((nf+1)/2) * W/nf * 0.29'" 
pd="'2*int((nf+1)/2) * (W/nf + 0.29)'"
as="'int((nf+2)/2) * W/nf * 0.29'" 
ps="'2*int((nf+2)/2) * (W/nf + 0.29)'"
nrd="'0.29 / W'" nrs="'0.29 / W'"
sa=0 sb=0 sd=0
model=nfet_01v8
spiceprefix=X
}
C {madvlsi/nmos3.sym} -10 440 1 0 {name=M150
L=\{L\}
W=\{W/2\}
body=GND
nf=1
mult=1
ad="'int((nf+1)/2) * W/nf * 0.29'" 
pd="'2*int((nf+1)/2) * (W/nf + 0.29)'"
as="'int((nf+2)/2) * W/nf * 0.29'" 
ps="'2*int((nf+2)/2) * (W/nf + 0.29)'"
nrd="'0.29 / W'" nrs="'0.29 / W'"
sa=0 sb=0 sd=0
model=nfet_01v8
spiceprefix=X
}
C {madvlsi/gnd.sym} -450 460 0 0 {name=l32 lab=GND}
C {madvlsi/gnd.sym} -130 460 0 0 {name=l34 lab=GND}
C {madvlsi/vdd.sym} 100 180 0 0 {name=l35 lab=VDD}
C {madvlsi/nmos3.sym} 70 440 1 0 {name=M25
L=\{L\}
W=\{W/2\}
body=GND
nf=1
mult=1
ad="'int((nf+1)/2) * W/nf * 0.29'" 
pd="'2*int((nf+1)/2) * (W/nf + 0.29)'"
as="'int((nf+2)/2) * W/nf * 0.29'" 
ps="'2*int((nf+2)/2) * (W/nf + 0.29)'"
nrd="'0.29 / W'" nrs="'0.29 / W'"
sa=0 sb=0 sd=0
model=nfet_01v8
spiceprefix=X
}
C {devices/opin.sym} -1070 370 0 0 {name=p1 lab=VBN}
C {devices/opin.sym} -940 20 0 0 {name=p2 lab=VOUT}
C {devices/opin.sym} 100 270 0 0 {name=p3 lab=VIN}
C {devices/opin.sym} -1830 540 1 0 {name=p4 lab=ROUT}
